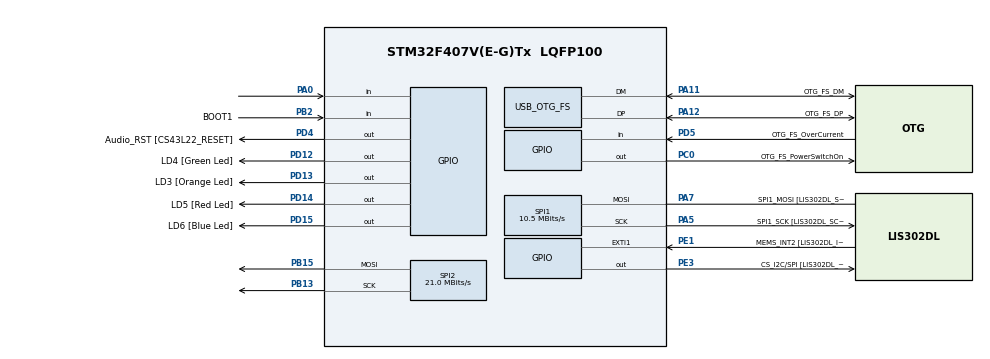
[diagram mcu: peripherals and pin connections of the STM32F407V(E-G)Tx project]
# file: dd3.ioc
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Dma.Request0=SPI2_TX
Dma.SPI2_TX.0.Channel=DMA_CHANNEL_0
Dma.SPI2_TX.0.Direction=DMA_MEMORY_TO_PERIPH
Dma.SPI2_TX.0.FIFOMode=DMA_FIFOMODE_DISABLE
Dma.SPI2_TX.0.Instance=DMA1_Stream4
Dma.SPI2_TX.0.MemDataAlignment=DMA_MDATAALIGN_BYTE
Dma.SPI2_TX.0.MemInc=DMA_MINC_ENABLE
Dma.SPI2_TX.0.Mode=DMA_NORMAL
Dma.SPI2_TX.0.PeriphDataAlignment=DMA_PDATAALIGN_BYTE
Dma.SPI2_TX.0.PeriphInc=DMA_PINC_DISABLE
Dma.SPI2_TX.0.Priority=DMA_PRIORITY_MEDIUM
FATFS._FS_NORTC=1
Mcu.Family=STM32F4
Mcu.Name=STM32F407V(E-G)Tx
Mcu.Package=LQFP100
NVIC.DMA1_Stream4_IRQn=true\:0\:0\:false\:false\:true
NVIC.OTG_FS_IRQn=true\:0\:0\:false\:false\:true
NVIC.PriorityGroup=NVIC_PRIORITYGROUP_4
NVIC.TIM3_IRQn=true\:0\:0\:false\:false\:true
NVIC.TIM4_IRQn=true\:0\:0\:false\:false\:true
PA0-WKUP.Signal=GPIO_Input
PA10.GPIO_Label=OTG_FS_ID
PA10.GPIO_Mode=GPIO_MODE_AF_PP
PA10.GPIO_PuPd=GPIO_NOPULL
PA10.GPIO_Speed=GPIO_SPEED_FREQ_LOW
PA10.Signal=USB_OTG_FS_ID
PA11.GPIO_Label=OTG_FS_DM
PA11.GPIO_Mode=GPIO_MODE_AF_PP
PA11.GPIO_PuPd=GPIO_NOPULL
PA11.GPIO_Speed=GPIO_SPEED_FREQ_LOW
PA11.Mode=Host_Only
PA11.Signal=USB_OTG_FS_DM
PA12.GPIO_Label=OTG_FS_DP
PA12.GPIO_Mode=GPIO_MODE_AF_PP
PA12.GPIO_PuPd=GPIO_NOPULL
PA12.GPIO_Speed=GPIO_SPEED_FREQ_LOW
PA12.Mode=Host_Only
PA12.Signal=USB_OTG_FS_DP
PA13.GPIO_Label=SWDIO
PA13.Signal=SYS_JTMS-SWDIO
PA14.GPIO_Label=SWCLK
PA14.Signal=SYS_JTCK-SWCLK
PA4.GPIO_Label=I2S3_WS [CS43L22_LRCK]
PA4.GPIO_Mode=GPIO_MODE_AF_PP
PA4.GPIO_PuPd=GPIO_NOPULL
PA4.GPIO_Speed=GPIO_SPEED_FREQ_LOW
PA4.Signal=I2S3_WS
PA5.GPIO_Label=SPI1_SCK [LIS302DL_SCL/SPC]
PA5.GPIO_Mode=GPIO_MODE_AF_PP
PA5.GPIO_PuPd=GPIO_NOPULL
PA5.GPIO_Speed=GPIO_SPEED_FREQ_LOW
PA5.Mode=Simplex_Bidirectional_Master
PA5.Signal=SPI1_SCK
PA6.GPIO_Label=SPI1_MISO [LIS302DL_SDO]
PA6.GPIO_Mode=GPIO_MODE_AF_PP
PA6.GPIO_PuPd=GPIO_NOPULL
PA6.GPIO_Speed=GPIO_SPEED_FREQ_LOW
PA6.Signal=SPI1_MISO
PA7.GPIO_Label=SPI1_MOSI [LIS302DL_SDA/SDI/SDO]
PA7.GPIO_Mode=GPIO_MODE_AF_PP
PA7.GPIO_PuPd=GPIO_NOPULL
PA7.GPIO_Speed=GPIO_SPEED_FREQ_LOW
PA7.Mode=Simplex_Bidirectional_Master
PA7.Signal=SPI1_MOSI
PA9.GPIO_Label=VBUS_FS
PA9.GPIO_Mode=GPIO_MODE_INPUT
PA9.GPIO_PuPd=GPIO_NOPULL
PA9.Signal=USB_OTG_FS_VBUS
PB10.GPIO_Label=CLK_IN [MP45DT02_CLK]
PB10.GPIO_Mode=GPIO_MODE_AF_PP
PB10.GPIO_PuPd=GPIO_NOPULL
PB10.GPIO_Speed=GPIO_SPEED_FREQ_LOW
PB10.Signal=I2S2_CK
PB13.Mode=TX_Only_Simplex_Unidirect_Master
PB13.Signal=SPI2_SCK
PB15.Mode=TX_Only_Simplex_Unidirect_Master
PB15.Signal=SPI2_MOSI
PB2.GPIO_Label=BOOT1
PB2.GPIO_Mode=GPIO_MODE_INPUT
PB2.GPIO_PuPd=GPIO_NOPULL
PB2.Signal=GPIO_Input
PB3.GPIO_Label=SWO
PB3.Signal=SYS_JTDO-SWO
PB6.GPIO_Label=Audio_SCL [CS43L22_SCL]
PB6.GPIO_Mode=GPIO_MODE_AF_OD
PB6.GPIO_PuPd=GPIO_NOPULL
PB6.GPIO_Speed=GPIO_SPEED_FREQ_LOW
PB6.Signal=I2C1_SCL
PB9.GPIO_Label=Audio_SDA [CS43L22_SDA]
PB9.GPIO_Mode=GPIO_MODE_AF_OD
PB9.GPIO_PuPd=GPIO_NOPULL
PB9.GPIO_Speed=GPIO_SPEED_FREQ_LOW
PB9.Signal=I2C1_SDA
PC0.GPIO_Label=OTG_FS_PowerSwitchOn
PC0.GPIO_PuPd=GPIO_NOPULL
PC0.GPIO_Speed=GPIO_SPEED_FREQ_LOW
PC0.Signal=GPIO_Output
PC10.GPIO_Label=I2S3_SCK [CS43L22_SCLK]
PC10.GPIO_Mode=GPIO_MODE_AF_PP
PC10.GPIO_PuPd=GPIO_NOPULL
PC10.GPIO_Speed=GPIO_SPEED_FREQ_LOW
PC10.Signal=I2S3_CK
PC12.GPIO_Label=I2S3_SD [CS43L22_SDIN]
PC12.GPIO_Mode=GPIO_MODE_AF_PP
PC12.GPIO_PuPd=GPIO_NOPULL
PC12.GPIO_Speed=GPIO_SPEED_FREQ_LOW
PC12.Signal=I2S3_SD
PC14-OSC32_IN.GPIO_Label=PC14-OSC32_IN
PC14-OSC32_IN.Signal=RCC_OSC32_IN
PC15-OSC32_OUT.GPIO_Label=PC15-OSC32_OUT
PC15-OSC32_OUT.Signal=RCC_OSC32_OUT
PC3.GPIO_Label=PDM_OUT [MP45DT02_DOUT]
PC3.GPIO_Mode=GPIO_MODE_AF_PP
PC3.GPIO_PuPd=GPIO_NOPULL
PC3.GPIO_Speed=GPIO_SPEED_FREQ_LOW
PC3.Signal=I2S2_SD
PC7.GPIO_Label=I2S3_MCK [CS43L22_MCLK]
PC7.GPIO_Mode=GPIO_MODE_AF_PP
PC7.GPIO_PuPd=GPIO_NOPULL
PC7.GPIO_Speed=GPIO_SPEED_FREQ_LOW
PC7.Signal=I2S3_MCK
PD12.GPIO_Label=LD4 [Green Led]
PD12.GPIO_PuPd=GPIO_NOPULL
PD12.GPIO_Speed=GPIO_SPEED_FREQ_LOW
PD12.Signal=GPIO_Output
PD13.GPIO_Label=LD3 [Orange Led]
PD13.GPIO_PuPd=GPIO_NOPULL
PD13.GPIO_Speed=GPIO_SPEED_FREQ_LOW
PD13.Signal=GPIO_Output
PD14.GPIO_Label=LD5 [Red Led]
PD14.GPIO_PuPd=GPIO_NOPULL
PD14.GPIO_Speed=GPIO_SPEED_FREQ_LOW
PD14.Signal=GPIO_Output
PD15.GPIO_Label=LD6 [Blue Led]
PD15.GPIO_PuPd=GPIO_NOPULL
PD15.GPIO_Speed=GPIO_SPEED_FREQ_LOW
PD15.Signal=GPIO_Output
PD4.GPIO_Label=Audio_RST [CS43L22_RESET]
PD4.GPIO_PuPd=GPIO_NOPULL
PD4.GPIO_Speed=GPIO_SPEED_FREQ_LOW
PD4.Signal=GPIO_Output
PD5.GPIO_Label=OTG_FS_OverCurrent
PD5.GPIO_Mode=GPIO_MODE_INPUT
PD5.GPIO_PuPd=GPIO_NOPULL
PD5.Signal=GPIO_Input
PE1.GPIO_Label=MEMS_INT2 [LIS302DL_INT2]
PE1.GPIO_ModeDefaultEXTI=GPIO_MODE_EVT_RISING
PE1.GPIO_PuPd=GPIO_NOPULL
PE1.Signal=GPXTI1
PE3.GPIO_Label=CS_I2C/SPI [LIS302DL_CS_I2C/SPI]
PE3.GPIO_PuPd=GPIO_NOPULL
PE3.GPIO_Speed=GPIO_SPEED_FREQ_LOW
PE3.Signal=GPIO_Output
PH0-OSC_IN.GPIO_Label=PH0-OSC_IN
PH0-OSC_IN.Mode=HSE-External-Oscillator
PH0-OSC_IN.Signal=RCC_OSC_IN
PH1-OSC_OUT.GPIO_Label=PH1-OSC_OUT
PH1-OSC_OUT.Mode=HSE-External-Oscillator
PH1-OSC_OUT.Signal=RCC_OSC_OUT
ProjectManager.HeapSize=0x200
ProjectManager.StackSize=0x400
ProjectManager.TargetToolchain=SW4STM32
RCC.48MHZClocksFreq_Value=48000000
RCC.AHBFreq_Value=168000000
RCC.APB1CLKDivider=RCC_HCLK_DIV4
RCC.APB1Freq_Value=42000000
RCC.APB1TimFreq_Value=84000000
RCC.APB2CLKDivider=RCC_HCLK_DIV8
RCC.APB2Freq_Value=21000000
RCC.APB2TimFreq_Value=42000000
RCC.CortexFreq_Value=168000000
RCC.HCLKFreq_Value=168000000
RCC.HSE_VALUE=8000000
RCC.HSI_VALUE=16000000
RCC.LSE_VALUE=1000000
RCC.PLLM=4
RCC.PLLN=168
RCC.PLLQ=7
RCC.SYSCLKFreq_VALUE=168000000
RCC.SYSCLKSource=RCC_SYSCLKSOURCE_PLLCLK
RCC.VCOOutputFreq_Value=336000000
SPI1.CalculateBaudRate=10.5 MBits/s
SPI1.Direction=SPI_DIRECTION_1LINE
SPI1.Mode=SPI_MODE_MASTER
SPI2.BaudRatePrescaler=SPI_BAUDRATEPRESCALER_2
SPI2.CalculateBaudRate=21.0 MBits/s
SPI2.Mode=SPI_MODE_MASTER
TIM3.CounterMode=TIM_COUNTERMODE_DOWN
TIM3.Period=2
TIM3.Prescaler=42000
TIM4.CounterMode=TIM_COUNTERMODE_DOWN
TIM4.Period=20
TIM4.Prescaler=42000
USB_HOST.USBH_HandleTypeDef-MSC_FS=hUsbHostFS
USB_HOST.VirtualModeFS=Msc
USB_OTG_FS.phy_itface=HCD_PHY_EMBEDDED
VP_FATFS_VS_USB.Mode=USB
VP_TIM3_VS_ClockSourceINT.Mode=Internal
VP_TIM4_VS_ClockSourceINT.Mode=Internal
VP_USB_HOST_VS_USB_HOST_MSC_FS.Mode=MSC_FS
board=STM32F4DISCOVERY

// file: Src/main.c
/**
  ******************************************************************************
  * File Name          : main.c
  * Description        : Main program body
  ******************************************************************************
  *
  * COPYRIGHT(c) 2016 STMicroelectronics
  *
  * Redistribution and use in source and binary forms, with or without modification,
  * are permitted provided that the following conditions are met:
  *   1. Redistributions of source code must retain the above copyright notice,
  *      this list of conditions and the following disclaimer.
  *   2. Redistributions in binary form must reproduce the above copyright notice,
  *      this list of conditions and the following disclaimer in the documentation
  *      and/or other materials provided with the distribution.
  *   3. Neither the name of STMicroelectronics nor the names of its contributors
  *      may be used to endorse or promote products derived from this software
  *      without specific prior written permission.
  *
  * THIS SOFTWARE IS PROVIDED BY THE COPYRIGHT HOLDERS AND CONTRIBUTORS "AS IS"
  * AND ANY EXPRESS OR IMPLIED WARRANTIES, INCLUDING, BUT NOT LIMITED TO, THE
  * IMPLIED WARRANTIES OF MERCHANTABILITY AND FITNESS FOR A PARTICULAR PURPOSE ARE
  * DISCLAIMED. IN NO EVENT SHALL THE COPYRIGHT HOLDER OR CONTRIBUTORS BE LIABLE
  * FOR ANY DIRECT, INDIRECT, INCIDENTAL, SPECIAL, EXEMPLARY, OR CONSEQUENTIAL
  * DAMAGES (INCLUDING, BUT NOT LIMITED TO, PROCUREMENT OF SUBSTITUTE GOODS OR
  * SERVICES; LOSS OF USE, DATA, OR PROFITS; OR BUSINESS INTERRUPTION) HOWEVER
  * CAUSED AND ON ANY THEORY OF LIABILITY, WHETHER IN CONTRACT, STRICT LIABILITY,
  * OR TORT (INCLUDING NEGLIGENCE OR OTHERWISE) ARISING IN ANY WAY OUT OF THE USE
  * OF THIS SOFTWARE, EVEN IF ADVISED OF THE POSSIBILITY OF SUCH DAMAGE.
  *
  ******************************************************************************
  */
#include "stm32f4xx_hal.h"
#include "fatfs.h"
#include "usb_host.h"

/* USER CODE BEGIN Includes */
#include <stdbool.h>
#include <stdio.h>

#include "apa_led.h"
#include "fk_pixels.h"

#include "app.h"

#define LINE_BY_LINE_
/* USER CODE END Includes */

SPI_HandleTypeDef hspi1;
SPI_HandleTypeDef hspi2;
DMA_HandleTypeDef hdma_spi2_tx;

TIM_HandleTypeDef htim3;
TIM_HandleTypeDef htim4;

/* USER CODE BEGIN PV */
/* Private variables ---------------------------------------------------------*/
uint8_t c_led = 0;
bool dir = 1;
uint8_t no_of_files = 0;
uint8_t c_file = 0;

bool has_selected_file = false;
/* USER CODE END PV */

void SystemClock_Config(void);
static void MX_GPIO_Init(void);
static void MX_DMA_Init(void);
static void MX_SPI1_Init(void);
static void MX_TIM4_Init(void);
static void MX_TIM3_Init(void);
static void MX_SPI2_Init(void);
void MX_USB_HOST_Process(void);

/* USER CODE BEGIN PFP */
/* Private function prototypes -----------------------------------------------*/
void led_kitt_scanner(void);

/* USER CODE END PFP */

int main(void)
{

  /* USER CODE BEGIN 1 */
   Appli_state = APPLICATION_IDLE;
  /* USER CODE END 1 */

  /* MCU Configuration----------------------------------------------------------*/

  /* Reset of all peripherals, Initializes the Flash interface and the Systick. */
  HAL_Init();

  /* Configure the system clock */
  SystemClock_Config();

  /* Initialize all configured peripherals */
  MX_GPIO_Init();
  MX_DMA_Init();
  MX_SPI1_Init();
  MX_TIM4_Init();
  MX_FATFS_Init();
  MX_USB_HOST_Init();
  MX_TIM3_Init();
  MX_SPI2_Init();

  /* USER CODE BEGIN 2 */
  /* Enable and set EXTI Line0 Interrupt to the lowest priority */
  //HAL_NVIC_SetPriority(EXTI0_IRQn, 0x0f, 0);
  //HAL_NVIC_EnableIRQ(EXTI0_IRQn);

  initLedFrame();
  sendLedData(&hspi2);
  //HAL_TIM_Base_Start_IT(&htim4);
  //HAL_TIM_Base_Start_IT(&htim3);

  /* USER CODE END 2 */

  /* Infinite loop */

  while (1)
  {
    MX_USB_HOST_Process();

  /* USER CODE BEGIN 3 */

  switch(Appli_state) {
    case APPLICATION_READY:
      if(f_mount(&USBDISKFatFs, (TCHAR const*) USBH_Path, 0) != FR_OK){
          setLed(NO_OF_LEDS-1, 100,0,0);
      }
      no_of_files = listDir();
      setLed(no_of_files, 0, 40, 0);
      //HAL_TIM_Base_Start_IT(&htim4);

      /*
      if(!has_image){
        if(fk_load_image()){
        // start timer3
        HAL_TIM_Base_Start_IT(&htim3);

        }
      }
      */
      Appli_state = APPLICATION_SELECT_FILE;
      sendLedData(&hspi2);
      break;
    case APPLICATION_SELECT_FILE:
      if(HAL_GPIO_ReadPin(GPIOA, GPIO_PIN_0)){
        if(c_file>0)
          setLed(c_file-1, 0, 0, 0);
        else
          setLed(no_of_files-1, 0, 0, 0);

        setLed(c_file, 10, 0, 0);
        sendLedData(&hspi2);
        HAL_Delay(200);
        if(HAL_GPIO_ReadPin(GPIOA, GPIO_PIN_0)){
          // Load pictura
          has_selected_file =true;
        } else {
          c_file++;
          if(c_file==no_of_files)
            c_file = 0;
        }
      }

      if (has_selected_file){
          has_selected_file =false;
#ifdef LINE_BY_LINE
          if(fk_open_line_nr(c_file))
#else
          if(fk_load_image_nr(c_file))
#endif
          {
            Appli_state = APPLICATION_IDLE;
            //HAL_TIM_Base_Stop_IT(&htim4);
            HAL_TIM_Base_Start_IT(&htim3);
          } else {
            setLed(143, 100, 0, 0);setLed(142, 100, 0, 0);setLed(141, 100, 0, 0);
            sendLedData(&hspi2);
          }
      }
      break;
    default:
      break;
  }
  /* USER CODE END 3 */
  }
}

/** System Clock Configuration
*/
void SystemClock_Config(void)
{

  RCC_OscInitTypeDef RCC_OscInitStruct;
  RCC_ClkInitTypeDef RCC_ClkInitStruct;

  __HAL_RCC_PWR_CLK_ENABLE();

  __HAL_PWR_VOLTAGESCALING_CONFIG(PWR_REGULATOR_VOLTAGE_SCALE1);

  RCC_OscInitStruct.OscillatorType = RCC_OSCILLATORTYPE_HSE;
  RCC_OscInitStruct.HSEState = RCC_HSE_ON;
  RCC_OscInitStruct.PLL.PLLState = RCC_PLL_ON;
  RCC_OscInitStruct.PLL.PLLSource = RCC_PLLSOURCE_HSE;
  RCC_OscInitStruct.PLL.PLLM = 4;
  RCC_OscInitStruct.PLL.PLLN = 168;
  RCC_OscInitStruct.PLL.PLLP = RCC_PLLP_DIV2;
  RCC_OscInitStruct.PLL.PLLQ = 7;
  HAL_RCC_OscConfig(&RCC_OscInitStruct);

  RCC_ClkInitStruct.ClockType = RCC_CLOCKTYPE_HCLK|RCC_CLOCKTYPE_SYSCLK
                              |RCC_CLOCKTYPE_PCLK1|RCC_CLOCKTYPE_PCLK2;
  RCC_ClkInitStruct.SYSCLKSource = RCC_SYSCLKSOURCE_PLLCLK;
  RCC_ClkInitStruct.AHBCLKDivider = RCC_SYSCLK_DIV1;
  RCC_ClkInitStruct.APB1CLKDivider = RCC_HCLK_DIV8;
  RCC_ClkInitStruct.APB2CLKDivider = RCC_HCLK_DIV8;
  HAL_RCC_ClockConfig(&RCC_ClkInitStruct, FLASH_LATENCY_5);

  HAL_SYSTICK_Config(HAL_RCC_GetHCLKFreq()/1000);

  HAL_SYSTICK_CLKSourceConfig(SYSTICK_CLKSOURCE_HCLK);

  /* SysTick_IRQn interrupt configuration */
  HAL_NVIC_SetPriority(SysTick_IRQn, 0, 0);
}

/* SPI1 init function */
void MX_SPI1_Init(void)
{

  hspi1.Instance = SPI1;
  hspi1.Init.Mode = SPI_MODE_MASTER;
  hspi1.Init.Direction = SPI_DIRECTION_1LINE;
  hspi1.Init.DataSize = SPI_DATASIZE_8BIT;
  hspi1.Init.CLKPolarity = SPI_POLARITY_LOW;
  hspi1.Init.CLKPhase = SPI_PHASE_1EDGE;
  hspi1.Init.NSS = SPI_NSS_SOFT;
  hspi1.Init.BaudRatePrescaler = SPI_BAUDRATEPRESCALER_2;
  hspi1.Init.FirstBit = SPI_FIRSTBIT_MSB;
  hspi1.Init.TIMode = SPI_TIMODE_DISABLE;
  hspi1.Init.CRCCalculation = SPI_CRCCALCULATION_DISABLE;
  hspi1.Init.CRCPolynomial = 10;
  HAL_SPI_Init(&hspi1);

}

/* SPI2 init function */
void MX_SPI2_Init(void)
{

  hspi2.Instance = SPI2;
  hspi2.Init.Mode = SPI_MODE_MASTER;
  hspi2.Init.Direction = SPI_DIRECTION_2LINES;
  hspi2.Init.DataSize = SPI_DATASIZE_8BIT;
  hspi2.Init.CLKPolarity = SPI_POLARITY_LOW;
  hspi2.Init.CLKPhase = SPI_PHASE_1EDGE;
  hspi2.Init.NSS = SPI_NSS_SOFT;
  hspi2.Init.BaudRatePrescaler = SPI_BAUDRATEPRESCALER_2;
  hspi2.Init.FirstBit = SPI_FIRSTBIT_MSB;
  hspi2.Init.TIMode = SPI_TIMODE_DISABLE;
  hspi2.Init.CRCCalculation = SPI_CRCCALCULATION_DISABLE;
  hspi2.Init.CRCPolynomial = 10;
  HAL_SPI_Init(&hspi2);

}

/* TIM3 init function */
void MX_TIM3_Init(void)
{

  TIM_ClockConfigTypeDef sClockSourceConfig;
  TIM_MasterConfigTypeDef sMasterConfig;

  htim3.Instance = TIM3;
  htim3.Init.Prescaler = 42000;
  htim3.Init.CounterMode = TIM_COUNTERMODE_DOWN;
  htim3.Init.Period = 2;
  htim3.Init.ClockDivision = TIM_CLOCKDIVISION_DIV1;
  HAL_TIM_Base_Init(&htim3);

  sClockSourceConfig.ClockSource = TIM_CLOCKSOURCE_INTERNAL;
  HAL_TIM_ConfigClockSource(&htim3, &sClockSourceConfig);

  sMasterConfig.MasterOutputTrigger = TIM_TRGO_RESET;
  sMasterConfig.MasterSlaveMode = TIM_MASTERSLAVEMODE_DISABLE;
  HAL_TIMEx_MasterConfigSynchronization(&htim3, &sMasterConfig);

}

/* TIM4 init function */
void MX_TIM4_Init(void)
{

  TIM_ClockConfigTypeDef sClockSourceConfig;
  TIM_MasterConfigTypeDef sMasterConfig;

  htim4.Instance = TIM4;
  htim4.Init.Prescaler = 42000;
  htim4.Init.CounterMode = TIM_COUNTERMODE_DOWN;
  htim4.Init.Period = 500;
  htim4.Init.ClockDivision = TIM_CLOCKDIVISION_DIV1;
  HAL_TIM_Base_Init(&htim4);

  sClockSourceConfig.ClockSource = TIM_CLOCKSOURCE_INTERNAL;
  HAL_TIM_ConfigClockSource(&htim4, &sClockSourceConfig);

  sMasterConfig.MasterOutputTrigger = TIM_TRGO_RESET;
  sMasterConfig.MasterSlaveMode = TIM_MASTERSLAVEMODE_DISABLE;
  HAL_TIMEx_MasterConfigSynchronization(&htim4, &sMasterConfig);

}

void MX_DMA_Init(void)
{
  /* DMA controller clock enable */
  __HAL_RCC_DMA1_CLK_ENABLE();

  /* DMA interrupt init */
  /* DMA1_Stream4_IRQn interrupt configuration */
  HAL_NVIC_SetPriority(DMA1_Stream4_IRQn, 0, 0);
  HAL_NVIC_EnableIRQ(DMA1_Stream4_IRQn);

}

/** Configure pins as
        * Analog
        * Input
        * Output
        * EVENT_OUT
        * EXTI
     PC3   ------> I2S2_SD
     PA4   ------> I2S3_WS
     PB10   ------> I2S2_CK
     PC7   ------> I2S3_MCK
     PC10   ------> I2S3_CK
     PC12   ------> I2S3_SD
     PB6   ------> I2C1_SCL
     PB9   ------> I2C1_SDA
*/
void MX_GPIO_Init(void)
{

  GPIO_InitTypeDef GPIO_InitStruct;

  /* GPIO Ports Clock Enable */
  __HAL_RCC_GPIOE_CLK_ENABLE();
  __HAL_RCC_GPIOC_CLK_ENABLE();
  __HAL_RCC_GPIOH_CLK_ENABLE();
  __HAL_RCC_GPIOA_CLK_ENABLE();
  __HAL_RCC_GPIOB_CLK_ENABLE();
  __HAL_RCC_GPIOD_CLK_ENABLE();

  /*Configure GPIO pin Output Level */
  HAL_GPIO_WritePin(CS_I2C_SPI_GPIO_Port, CS_I2C_SPI_Pin, GPIO_PIN_RESET);

  /*Configure GPIO pin Output Level */
  HAL_GPIO_WritePin(OTG_FS_PowerSwitchOn_GPIO_Port, OTG_FS_PowerSwitchOn_Pin, GPIO_PIN_RESET);

  /*Configure GPIO pin Output Level */
  HAL_GPIO_WritePin(GPIOD, LD4_Pin|LD3_Pin|LD5_Pin|LD6_Pin
                          |Audio_RST_Pin, GPIO_PIN_RESET);

  /*Configure GPIO pin : CS_I2C_SPI_Pin */
  GPIO_InitStruct.Pin = CS_I2C_SPI_Pin;
  GPIO_InitStruct.Mode = GPIO_MODE_OUTPUT_PP;
  GPIO_InitStruct.Pull = GPIO_NOPULL;
  GPIO_InitStruct.Speed = GPIO_SPEED_FREQ_LOW;
  HAL_GPIO_Init(CS_I2C_SPI_GPIO_Port, &GPIO_InitStruct);

  /*Configure GPIO pin : OTG_FS_PowerSwitchOn_Pin */
  GPIO_InitStruct.Pin = OTG_FS_PowerSwitchOn_Pin;
  GPIO_InitStruct.Mode = GPIO_MODE_OUTPUT_PP;
  GPIO_InitStruct.Pull = GPIO_NOPULL;
  GPIO_InitStruct.Speed = GPIO_SPEED_FREQ_LOW;
  HAL_GPIO_Init(OTG_FS_PowerSwitchOn_GPIO_Port, &GPIO_InitStruct);

  /*Configure GPIO pin : PDM_OUT_Pin */
  GPIO_InitStruct.Pin = PDM_OUT_Pin;
  GPIO_InitStruct.Mode = GPIO_MODE_AF_PP;
  GPIO_InitStruct.Pull = GPIO_NOPULL;
  GPIO_InitStruct.Speed = GPIO_SPEED_FREQ_LOW;
  GPIO_InitStruct.Alternate = GPIO_AF5_SPI2;
  HAL_GPIO_Init(PDM_OUT_GPIO_Port, &GPIO_InitStruct);

  /*Configure GPIO pin : PA0 */
  GPIO_InitStruct.Pin = GPIO_PIN_0;
  GPIO_InitStruct.Mode = GPIO_MODE_INPUT;
  GPIO_InitStruct.Pull = GPIO_NOPULL;
  HAL_GPIO_Init(GPIOA, &GPIO_InitStruct);

  /*Configure GPIO pin : PA4 */
  GPIO_InitStruct.Pin = GPIO_PIN_4;
  GPIO_InitStruct.Mode = GPIO_MODE_AF_PP;
  GPIO_InitStruct.Pull = GPIO_NOPULL;
  GPIO_InitStruct.Speed = GPIO_SPEED_FREQ_LOW;
  GPIO_InitStruct.Alternate = GPIO_AF6_SPI3;
  HAL_GPIO_Init(GPIOA, &GPIO_InitStruct);

  /*Configure GPIO pin : BOOT1_Pin */
  GPIO_InitStruct.Pin = BOOT1_Pin;
  GPIO_InitStruct.Mode = GPIO_MODE_INPUT;
  GPIO_InitStruct.Pull = GPIO_NOPULL;
  HAL_GPIO_Init(BOOT1_GPIO_Port, &GPIO_InitStruct);

  /*Configure GPIO pin : CLK_IN_Pin */
  GPIO_InitStruct.Pin = CLK_IN_Pin;
  GPIO_InitStruct.Mode = GPIO_MODE_AF_PP;
  GPIO_InitStruct.Pull = GPIO_NOPULL;
  GPIO_InitStruct.Speed = GPIO_SPEED_FREQ_LOW;
  GPIO_InitStruct.Alternate = GPIO_AF5_SPI2;
  HAL_GPIO_Init(CLK_IN_GPIO_Port, &GPIO_InitStruct);

  /*Configure GPIO pins : LD4_Pin LD3_Pin LD5_Pin LD6_Pin
                           Audio_RST_Pin */
  GPIO_InitStruct.Pin = LD4_Pin|LD3_Pin|LD5_Pin|LD6_Pin
                          |Audio_RST_Pin;
  GPIO_InitStruct.Mode = GPIO_MODE_OUTPUT_PP;
  GPIO_InitStruct.Pull = GPIO_NOPULL;
  GPIO_InitStruct.Speed = GPIO_SPEED_FREQ_LOW;
  HAL_GPIO_Init(GPIOD, &GPIO_InitStruct);

  /*Configure GPIO pins : PC7 I2S3_SCK_Pin PC12 */
  GPIO_InitStruct.Pin = GPIO_PIN_7|I2S3_SCK_Pin|GPIO_PIN_12;
  GPIO_InitStruct.Mode = GPIO_MODE_AF_PP;
  GPIO_InitStruct.Pull = GPIO_NOPULL;
  GPIO_InitStruct.Speed = GPIO_SPEED_FREQ_LOW;
  GPIO_InitStruct.Alternate = GPIO_AF6_SPI3;
  HAL_GPIO_Init(GPIOC, &GPIO_InitStruct);

  /*Configure GPIO pin : OTG_FS_OverCurrent_Pin */
  GPIO_InitStruct.Pin = OTG_FS_OverCurrent_Pin;
  GPIO_InitStruct.Mode = GPIO_MODE_INPUT;
  GPIO_InitStruct.Pull = GPIO_NOPULL;
  HAL_GPIO_Init(OTG_FS_OverCurrent_GPIO_Port, &GPIO_InitStruct);

  /*Configure GPIO pins : Audio_SCL_Pin Audio_SDA_Pin */
  GPIO_InitStruct.Pin = Audio_SCL_Pin|Audio_SDA_Pin;
  GPIO_InitStruct.Mode = GPIO_MODE_AF_OD;
  GPIO_InitStruct.Pull = GPIO_PULLUP;
  GPIO_InitStruct.Speed = GPIO_SPEED_FREQ_LOW;
  GPIO_InitStruct.Alternate = GPIO_AF4_I2C1;
  HAL_GPIO_Init(GPIOB, &GPIO_InitStruct);

  /*Configure GPIO pin : MEMS_INT2_Pin */
  GPIO_InitStruct.Pin = MEMS_INT2_Pin;
  GPIO_InitStruct.Mode = GPIO_MODE_EVT_RISING;
  GPIO_InitStruct.Pull = GPIO_NOPULL;
  HAL_GPIO_Init(MEMS_INT2_GPIO_Port, &GPIO_InitStruct);

}
bool has_data = false;

/* USER CODE BEGIN 4 */
uint32_t delay;
void HAL_TIM_PeriodElapsedCallback(TIM_HandleTypeDef *htim)
{
  // Every 3ms
  if (htim->Instance == TIM3) {
    //led_kitt_scanner();
		HAL_GPIO_TogglePin(LD3_GPIO_Port, LD3_Pin);
    if (has_image){
#     ifdef LINE_BY_LINE
          if(has_data){
            for(uint8_t led=0;led<144;led++){
                uint32_t i = led*3;
                setLed(led, tmp[i+2], tmp[i+1], tmp[i]);
            }
            has_data = false;
          }

        //readline
        if(sendLine()){
            has_data = true;
        } else {
          setLed(60, 60, 0, 0);
        }
#     else
        loadRow();
#     endif

    }
    sendLedData(&hspi2);

  // Every 20ms
  } else if(htim->Instance == TIM4){

  }

}

void led_kitt_scanner(void)
{
    if(dir){
        c_led++;
        setLed(c_led, 100, 0, 0);
        if(c_led == NO_OF_LEDS) {
          dir = !dir;
        }
        if(c_led > 0)
          setLed(c_led-1, 0, 0, 0);

    } else {
        c_led--;
        setLed(c_led, 100, 0, 0);
        if(c_led == 0) {
          dir = !dir;
        }
        if (c_led<NO_OF_LEDS-1)
            setLed(c_led+1, 0, 0, 0);

    }
}
/* USER CODE END 4 */

/************************ (C) COPYRIGHT STMicroelectronics *****END OF FILE****/
